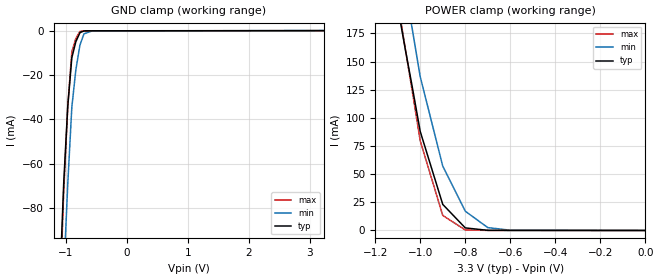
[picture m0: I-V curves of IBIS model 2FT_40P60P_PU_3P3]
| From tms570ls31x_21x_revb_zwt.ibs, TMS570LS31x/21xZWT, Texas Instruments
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|   Model Cell 2FT_40P60P_PU_3P3
|IQ0442FT_40P60P_PU_3P3
[Model]   2FT_40P60P_PU_3P3
Model_type   Input
Polarity   Non-Inverting
Vinl =  1.55
Vinh =  1.75
C_comp   1.2p   1.2p   1.2p
[Model Spec]
Vinl   1.55   1.42   1.68
Vinh   1.75   1.55   1.85
[Temperature Range]   25   155   -40
[Voltage Range]   3.3   2.97   3.63
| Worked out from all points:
|   GND clamp passes 1 mA (typ) near -0.77 V on its own axis
|   POWER clamp passes 1 mA (typ) near -0.74 V on its own axis
[POWER_clamp]
|   voltage   I(typ)   I(min)   I(max)
-3.3V     3.541A     4.385A     3.783A
-1.1V     198.7mA    255.1mA    203.5mA
-1.067V   161.8mA    215.6mA    162.2mA
-1.033V   124.9mA    176.1mA    120.9mA
-1V       87.97mA    136.6mA    79.61mA
-900mV    23.17mA    57.17mA    13.36mA
-800mV    2.295mA    17.13mA    436.4uA
-700mV    123.7uA    2.545mA    80.52uA
-600mV    48.23uA    249uA      65.13uA
0V        279pA      422.3pA    307.1pA
[GND_clamp]
|   voltage   I(typ)   I(min)   I(max)
-3.3V     -2.707A    -2.59A     -3.853A
-1.1V     -116mA     -158.3mA   -125mA
-1.033V   -68.85mA   -110.6mA   -72.8mA
-966.7mV  -34.26mA   -69.39mA   -34.34mA
-900mV    -12.25mA   -34.63mA   -9.585mA
-833.3mV  -4.968mA   -17.56mA   -3.52mA
-766.7mV  -930.9uA   -6.499mA   -373.3uA
-700mV    -139.3uA   -1.44mA    -144.6uA
-566.7mV  -87.77uA   -155.4uA   -139uA
3.233V    -4.592uA   11.82uA    -37.39uA
